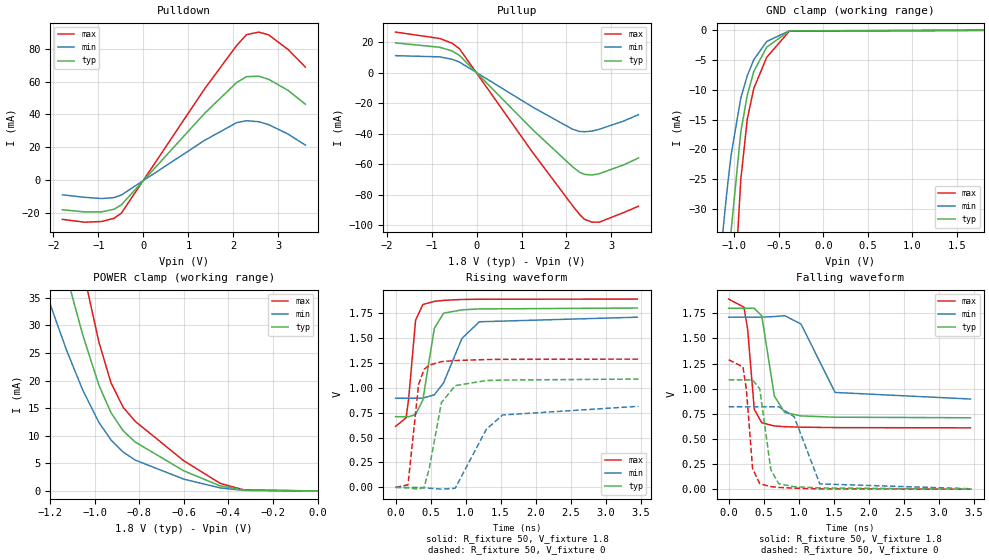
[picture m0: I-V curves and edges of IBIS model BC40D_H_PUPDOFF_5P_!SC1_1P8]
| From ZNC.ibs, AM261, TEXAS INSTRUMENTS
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[Model]   BC40D_H_PUPDOFF_5P_!SC1_1P8
Model_type   I/O
Polarity   Non-Inverting
Enable   Active-Low
Vinl =  0.63
Vinh =  1.17
Cref =  15pF
Rref =  100.0000M
Vref =  0V
Vmeas =  0.9
C_comp   2.364487p   2.290698p   2.389419p
|[Input load] weak_pupdoff
|[Output drive] fast
|[supplytol] 5
|[temp] ind
[Model Spec]
Vinl   0.63   0.5985   0.6615
Vinh   1.17   1.1115   1.2285
[Temperature Range]   25   125   -40
[Voltage Range]   1.8   1.71   1.89
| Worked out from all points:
|   slope of the pulldown table from 0 to 0.27 V, typ, clamps not added: 32.2 ohm
|   slope of the pullup table from 0 to 0.27 V, typ, clamps not added: 32.5 ohm
|   GND clamp passes 1 mA (typ) near -0.53 V on its own axis
|   POWER clamp passes 1 mA (typ) near -0.44 V on its own axis
|   rising waveform, R_fixture 50, V_fixture 1.8: 20-80 % time 145ps typ, 303ps min, 93.6ps max; typ from 0.709 V to 1.8 V
|   rising waveform, R_fixture 50, V_fixture 0: 20-80 % time 176ps typ, 352ps min, 106ps max; typ from 0 V to 1.09 V
|   falling waveform, R_fixture 50, V_fixture 1.8: 20-80 % time 130ps typ, 266ps min, 88.3ps max; typ from 1.8 V to 0.71 V
|   falling waveform, R_fixture 50, V_fixture 0: 20-80 % time 113ps typ, 198ps min, 84.5ps max; typ from 1.09 V to 0 V
| Nom Voltages:
|   VDD=1.1, VDDS=1.8, VDDS18=1.8, ESD_BIASFET=0, VSS=0, VSSS=0
| Min Voltages:
|   VDD=1.045, VDDS=1.71, VDDS18=1.71, ESD_BIASFET=0, VSS=0, VSSS=0
| Max Voltages:
|   VDD=1.16, VDDS=1.89, VDDS18=1.89, ESD_BIASFET=0, VSS=0, VSSS=0
[POWER_clamp]
|   voltage   I(typ)   I(min)   I(max)
-1.8V     158.8mA    112.5mA    219.7mA
-1.255V   59.93mA    39.99mA    84.86mA
-1.127V   39.08mA    25.5mA     55.75mA
-1.055V   28.36mA    18.34mA    40.41mA
-981.8mV  19.18mA    12.43mA    26.98mA
-927.3mV  14.16mA    9.239mA    19.58mA
-872.7mV  10.89mA    7.049mA    15.14mA
-818.2mV  8.843mA    5.579mA    12.59mA
-600mV    3.63mA     2.128mA    5.45mA
-436.4mV  903.9uA    539uA      1.358mA
-327.3mV  138.2uA    94.87uA    160.3uA
0V        19.3nA     133.7nA    230.3nA
[Pulldown]
|   voltage   I(typ)   I(min)   I(max)
-1.8V     -17.92mA   -8.85mA    -23.8mA
-1.309V   -19.26mA   -10.37mA   -25.5mA
-927.3mV  -19.22mA   -11.12mA   -25.08mA
-654.5mV  -17.65mA   -10.56mA   -23.13mA
-490.9mV  -14.97mA   -8.985mA   -20.05mA
1.364V    40.78mA    24.32mA    55.7mA
2.073V    59.41mA    35mA       81.91mA
2.291V    62.96mA    36.2mA     88.48mA
2.564V    63.25mA    35.58mA    90.07mA
2.782V    61.38mA    33.82mA    88.42mA
3.218V    54.59mA    28.02mA    79.45mA
3.6V      46.26mA    21.39mA    68.79mA
[Pullup]
|   voltage   I(typ)   I(min)   I(max)
-1.8V     19.47mA    11.11mA    26.55mA
-818.2mV  16.61mA    10.32mA    22.37mA
-545.5mV  14.21mA    8.765mA    19.31mA
-381.8mV  11.35mA    6.928mA    15.71mA
1.255V    -37.58mA   -22.7mA    -52.59mA
2.127V    -61.49mA   -36.97mA   -86.91mA
2.291V    -65.3mA    -38.55mA   -92.97mA
2.4V      -66.65mA   -38.72mA   -96.07mA
2.564V    -67.08mA   -38.3mA    -97.93mA
2.727V    -66.24mA   -37.15mA   -97.99mA
3.273V    -60.4mA    -31.68mA   -91.65mA
3.6V      -55.92mA   -27.55mA   -87.52mA
[GND_clamp]
|   voltage   I(typ)   I(min)   I(max)
-1.8V     -270.2mA   -170.2mA   -430.1mA
-1.255V   -91.66mA   -55.91mA   -148.4mA
-1.145V   -59.91mA   -36.45mA   -97.09mA
-1.109V   -50.48mA   -30.83mA   -81.55mA
-1.073V   -41.73mA   -25.65mA   -67.05mA
-1.036V   -33.66mA   -20.92mA   -53.59mA
-927.3mV  -17.07mA   -11.35mA   -25.04mA
-854.5mV  -10.86mA   -7.617mA   -14.91mA
-781.8mV  -6.919mA   -4.945mA   -9.771mA
-636.4mV  -2.823mA   -1.868mA   -4.529mA
-381.8mV  -84.73uA   -78.82uA   -126.1uA
1.8V      19.3nA     350.9nA    215.8nA
[Ramp]
| variable   typ   min   max
dV/dt_f 0.66537461/0.1328587n 0.49951599/0.27202412n  0.7771902/89.861739p
dV/dt_r  0.6647348/0.17860803n 0.51000261/0.36733301n 0.78144821/0.10715466n
R_load = 50
[Rising Waveform]
R_fixture = 50
V_fixture = 1.8
V_fixture_min = 1.71
V_fixture_max = 1.89
|   time   V(typ)   V(min)   V(max)
0s        709.2mV    894.4mV    611.3mV
151.7ps   709.2mV    894.4mV    699.2mV
187ps     709.2mV    894.4mV    887.5mV
285.9ps   730.7mV    894.4mV    1.677V
390.1ps   876.9mV    896.1mV    1.835V
553.8ps   1.596V     928.7mV    1.867V
686.1ps   1.748V     1.049V     1.877V
948.8ps   1.782V     1.496V     1.886V
1.197ns   1.791V     1.662V     1.888V
3.453ns   1.8V       1.708V     1.89V
[Rising Waveform]
R_fixture = 50
V_fixture = 0
V_fixture_min = 0
V_fixture_max = 0
|   time   V(typ)   V(min)   V(max)
0s        0V         0V         0V
177.7ps   -5.678mV   0V         25.83mV
328.8ps   -18.26mV   0V         1.031V
407.1ps   0V         -4.568mV   1.184V
481.7ps   192mV      -8.475mV   1.227V
655.2ps   850.1mV    -18.02mV   1.262V
852.1ps   1.021V     -9.072mV   1.273V
1.295ns   1.072V     580.9mV    1.283V
1.529ns   1.077V     726.3mV    1.285V
3.47ns    1.087V     813.6mV    1.287V
[Falling Waveform]
R_fixture = 50
V_fixture = 1.8
V_fixture_min = 1.71
V_fixture_max = 1.89
|   time   V(typ)   V(min)   V(max)
0s        1.799V     1.711V     1.891V
218.1ps   1.799V     1.711V     1.81V
270.7ps   1.799V     1.711V     1.592V
365.8ps   1.799V     1.711V     794.1mV
472.5ps   1.724V     1.711V     660.3mV
652.7ps   925.8mV    1.717V     629.1mV
801.2ps   762mV      1.726V     621.2mV
1.032ns   728.7mV    1.643V     616.6mV
1.52ns    715.8mV    962mV      612.3mV
3.453ns   710.3mV    896.7mV    610mV
[Falling Waveform]
R_fixture = 50
V_fixture = 0
V_fixture_min = 0
V_fixture_max = 0
|   time   V(typ)   V(min)   V(max)
0s        1.087V     819.6mV    1.287V
203.8ps   1.087V     819.6mV    1.216V
254.1ps   1.087V     819.6mV    983.5mV
341.4ps   1.087V     819.6mV    205.8mV
444.1ps   997.6mV    819.6mV    54.23mV
601.9ps   194.9mV    819.6mV    25.35mV
714.7ps   54.87mV    819.6mV    17.53mV
935.6ps   24.13mV    720mV      10.14mV
1.302ns   12.55mV    52.42mV    3.16mV
3.47ns    0V         4.122mV    0V
